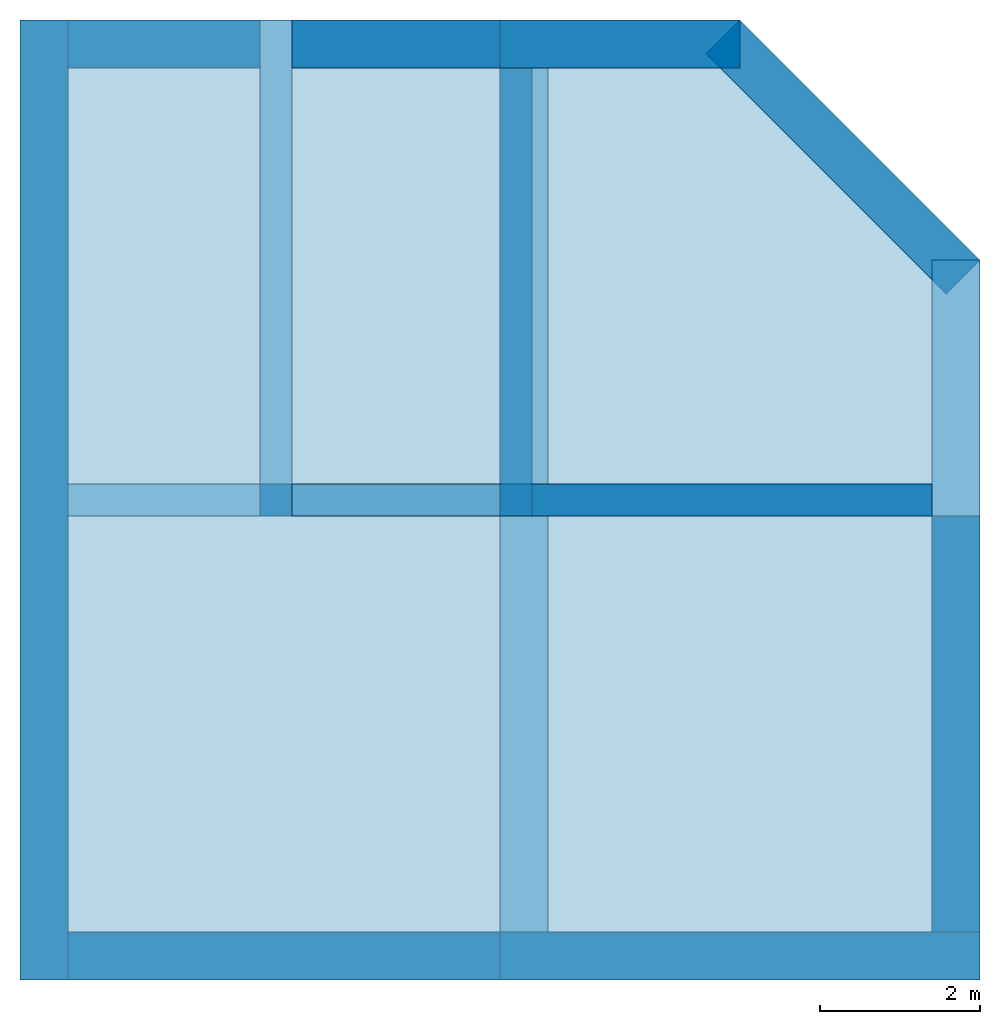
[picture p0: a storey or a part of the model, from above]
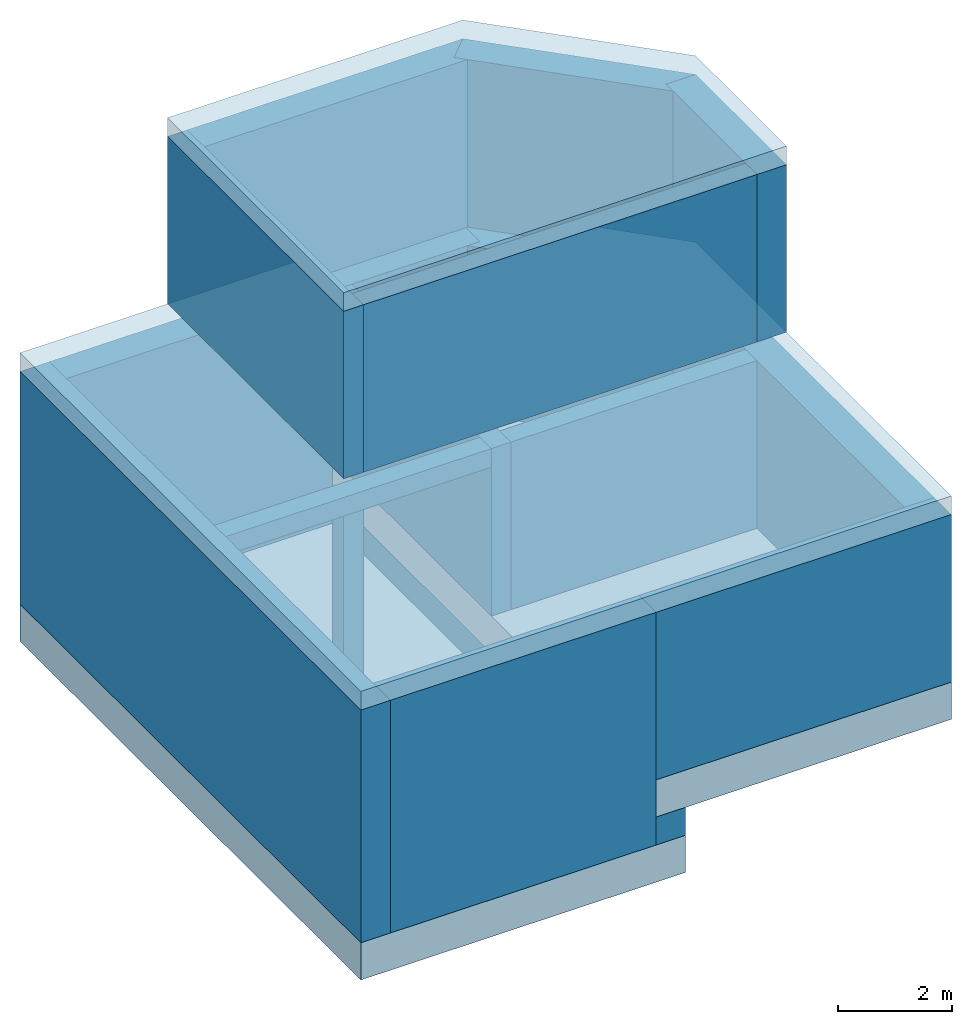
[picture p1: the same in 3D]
Properties of the parts of a building model (IFC2X3)

# File
Description: ViewDefinition[CoordinationView_V2.0, QuantityTakeOffAddOnView], Option [BaseQuantities:On], Option [GridExport:On], Option [Assemblies:On], Option [Bolts:On], Option [Rebars:On], Option [PourObjects:Off], Option [Welds:Off], Option [SurfaceTreatments:On], Option [LocationBy:0], Option [ViewColors:Off], Option [SectionedSpine:Off], Option [PropertySets:On], Option [Export all:Off]
File name: VTZ_geom_OPR.ifc
Time: 2024-01-23T14:21:08
Author: VNIPIET\18962017
Organization: Structural Designer
Written by: IFC Database version: Work
Made in: Tekla Structures 2021 Service Pack 11, IFC Export Version: 4.0.0.0 Nov 13 2022

# IfcBuildingStorey, Undefined
In: Undefined
Elevation: 0 mm

# IfcBeam: 400*400, BEAM
In: Undefined
Description: 400*400; Material: CONCRETE/B30_XC3
BaseQuantities - Length: 5400 mm; OuterSurfaceArea: 8.96 m2; NetVolume: 0.864 m3; NetWeight: 2030.4 kg

# IfcColumn: 400*400, COLUMN
In: Undefined
Description: 400*400; Material: CONCRETE/B30_XC3
BaseQuantities - Length: 4600 mm; OuterSurfaceArea: 7.68 m2; NetVolume: 0.736 m3; NetWeight: 1729.6 kg

# IfcElementAssembly (21)
In: Undefined
PredefinedType: REINFORCEMENT_UNIT
Name | Width (mm)
11 x Wall | 600
SLAB | 400
4 x Wall | 400
SLAB_Roof | 400
BEAM | 400
COLUMN | 400
2 x SLAB_Found | 800

# IfcSlab: 400*12000, SLAB_Roof
In: Undefined
Description: 400*12000; PredefinedType: FLOOR; Material: CONCRETE/B45_XA3,XS3_Sulphat
BaseQuantities - Width: 400 mm; NetVolume: 55.8 m3; NetArea: 139.5 m2; NetWeight: 131130 kg

# IfcSlab: 400*6200, SLAB
In: Undefined
Description: 400*6200; PredefinedType: FLOOR; Material: CONCRETE/B45_XA3,XS3_Sulphat
BaseQuantities - Width: 400 mm; NetVolume: 20.52 m3; NetArea: 51.3 m2; NetWeight: 48222 kg

# IfcSlab: 800*6000, SLAB_Found
In: Undefined
Description: 800*6000; PredefinedType: FLOOR; Material: CONCRETE/B45_XA3,XS3_Sulphat
BaseQuantities - Width: 800 mm; NetVolume: 54 m3; NetArea: 67.5 m2; NetWeight: 126900 kg

# IfcSlab: 800*6600, SLAB_Found
In: Undefined
Description: 800*6600; PredefinedType: FLOOR; Material: CONCRETE/B45_XA3,XS3_Sulphat
BaseQuantities - Width: 800 mm; NetVolume: 63.36 m3; NetArea: 79.2 m2; NetWeight: 148896 kg

# IfcWall: 3600*400 (4)
In: Undefined
Description: 3600*400
BaseQuantities - Width: 400 mm
Name | Material | Length (mm) | OuterSurfaceArea (m2) | NetVolume (m3) | NetWeight (kg) | GrossFootprintArea (m2)
Wall | CONCRETE/B45_XA3,XS3_Sulphat | 8000 | 66.88 | 11.52 | 27072 | 3.2
Wall | CONCRETE/B45_XA3,XS3_Sulphat | 6200 | 52.48 | 8.928 | 20980.8 | 2.48
Wall | CONCRETE/Concrete_Undefined | 5600 | 47.68 | 8.064 | 0 | 2.24
Wall | CONCRETE/Concrete_Undefined | 5000 | 42.88 | 7.2 | 0 | 2

# IfcWall: 3600*600 (7)
In: Undefined
Description: 3600*600
BaseQuantities - Width: 600 mm
Name | Material | Length (mm) | OuterSurfaceArea (m2) | NetVolume (m3) | NetWeight (kg) | GrossFootprintArea (m2)
Wall | CONCRETE/B45_XA3,XS3_Sulphat | 4242.64 | 39.9582 | 9.1641 | 21535.6 | 2.54558
Wall | CONCRETE/B45_XA3,XS3_Sulphat | 3200 | 31.2 | 6.912 | 16243.2 | 1.92
Wall | CONCRETE/B45_XA3,XS3_Sulphat | 5600 | 51.36 | 12.096 | 28425.6 | 3.36
Wall | CONCRETE/Concrete_Undefined | 8400 | 74.88 | 18.144 | 0 | 5.04
Wall | CONCRETE/Concrete_Undefined | 4242.64 | 39.9582 | 9.1641 | 0 | 2.54558
Wall | CONCRETE/Concrete_Undefined | 6000 | 54.72 | 12.96 | 0 | 3.6
Wall | CONCRETE/Concrete_Undefined | 3000 | 29.52 | 6.48 | 0 | 1.8

# IfcWall: 5000*600 (3)
In: Undefined
Description: 5000*600; Material: CONCRETE/Concrete_Undefined
BaseQuantities - NetWeight: 0 kg; Width: 600 mm
Name | Length (mm) | OuterSurfaceArea (m2) | NetVolume (m3) | GrossFootprintArea (m2)
2 x Wall | 5400 | 66.48 | 16.2 | 3.24
Wall | 12000 | 140.4 | 36 | 7.2

# IfcWall: 600*600, Wall
In: Undefined
Description: 600*600; Material: CONCRETE/B45_XA3,XS3_Sulphat
BaseQuantities - Length: 12000 mm; OuterSurfaceArea: 29.52 m2; NetVolume: 4.32 m3; NetWeight: 10152 kg; Width: 600 mm; GrossFootprintArea: 7.2 m2
